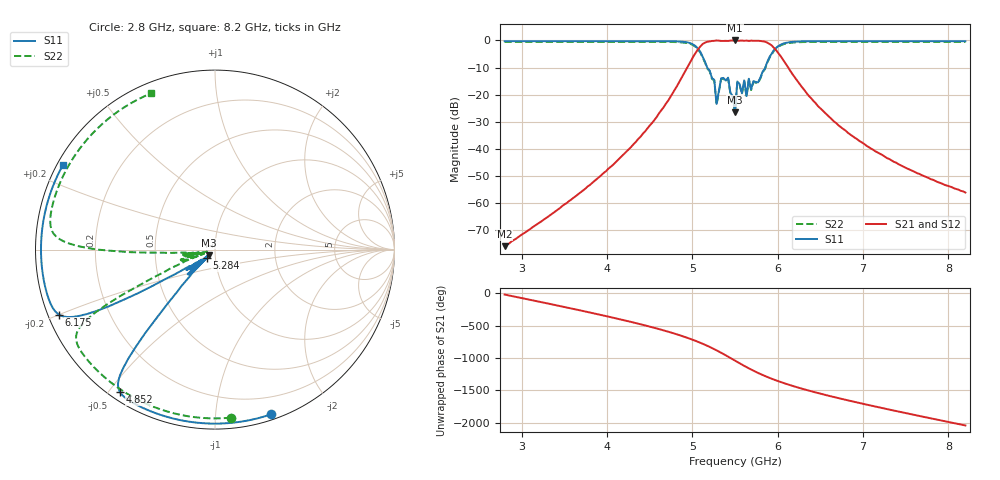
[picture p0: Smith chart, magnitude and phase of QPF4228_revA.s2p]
! written by passband
# GHZ S DB R 50
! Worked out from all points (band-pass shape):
!   201 points, 2.8 GHz to 8.2 GHz, reference 50 ohm
!   highest |S21| = -0.01 dB at 5.5 GHz (marker M1); lowest = -76.0 dB at 2.8 GHz (marker M2)
!   |S21| within 3 dB of the highest: 5.073 GHz to 5.964 GHz (891.6 MHz wide, 16.2 % of centre)
!   lowest |S11| = -26.5 dB at 5.5 GHz (marker M3), VSWR 1.10, Z = 46.4 - j2.81 ohm
!   |S11| at or under -10 dB: 5.174 GHz to 5.855 GHz (680.6 MHz wide, 12.3 % of centre)
!   |S22| runs from -26.8 to -0.5 dB; largest |S21 - S12| = 0
!   S11 on the Smith chart (normalised r, x): 2.8 GHz: 0.05, -1.39; 4.852 GHz: 0.03, -0.54; 5.284 GHz: 0.91, -0.09; 6.175 GHz: 0.03, -0.20; 8.2 GHz: 0.02, +0.26
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2.8  -0.27 -71.4  -75.98 -18.7  -75.98 -18.7  -0.53 -84.6
3.718  -0.27 -94.8  -55.45 87.2  -55.45 87.2  -0.53 -112.3
4.609  -0.28 -117.5  -26.95 167.4  -26.95 167.4  -0.54 -139.2
4.852  -0.41 -123.7  -15.05 72.2  -15.05 72.2  -0.67 -146.5
4.987  -1.14 -127.1  -7.41 10.7  -7.41 10.7  -1.40 -150.6
5.095  -4.29 -129.9  -2.19 -45.0  -2.19 -45.0  -4.55 -153.9
5.176  -10.16 -131.9  -0.47 -91.7  -0.47 -91.7  -10.42 -156.3
5.257  -14.55 -134.0  -0.17 -143.0  -0.17 -143.0  -14.81 -158.8
5.284  -23.44 -134.7  -0.02 -161.2  -0.02 -161.2  -23.70 -159.6
5.338  -13.98 -136.1  -0.19 161.0  -0.19 161.0  -14.25 -161.2
5.419  -13.76 -138.1  -0.20 101.2  -0.20 101.2  -14.02 -163.7
5.5  -26.54 -140.2  -0.01 39.4  -0.01 39.4  -26.81 -166.1
5.527  -15.16 -140.9  -0.14 18.9  -0.14 18.9  -15.42 -166.9
5.635  -20.56 -143.6  -0.04 -61.0  -0.04 -61.0  -20.82 -170.2
5.662  -14.15 -144.3  -0.18 -80.0  -0.18 -80.0  -14.42 -171.0
5.797  -13.79 -147.8  -0.20 -167.2  -0.20 -167.2  -14.06 -175.1
5.932  -4.79 -151.2  -1.89 118.3  -1.89 118.3  -5.05 -179.2
6.04  -1.51 -153.9  -6.04 66.3  -6.04 66.3  -1.78 177.6
6.175  -0.52 -157.4  -12.52 8.3  -12.52 8.3  -0.78 173.5
6.418  -0.29 -163.6  -22.32 -83.0  -22.32 -83.0  -0.56 166.2
7.309  -0.27 173.7  -43.80 2.2  -43.80 2.2  -0.53 139.3
8.2  -0.27 151.0  -56.17 117.0  -56.17 117.0  -0.53 112.4
